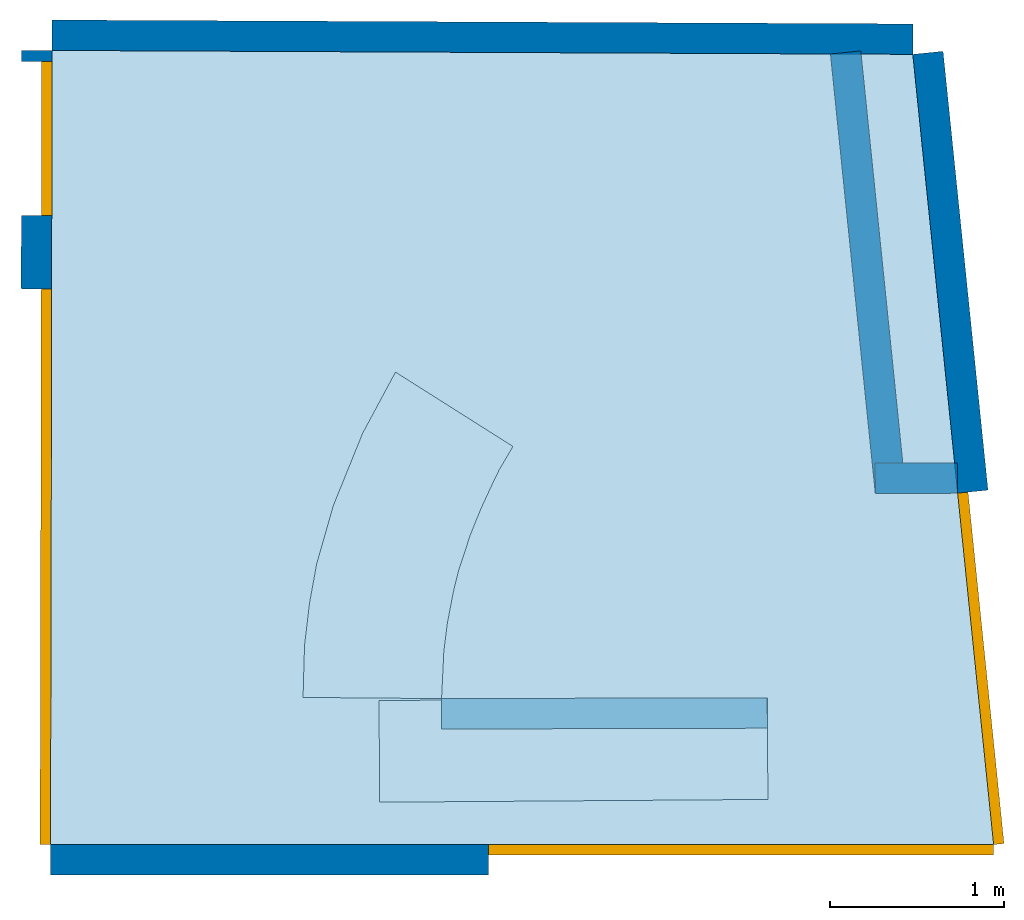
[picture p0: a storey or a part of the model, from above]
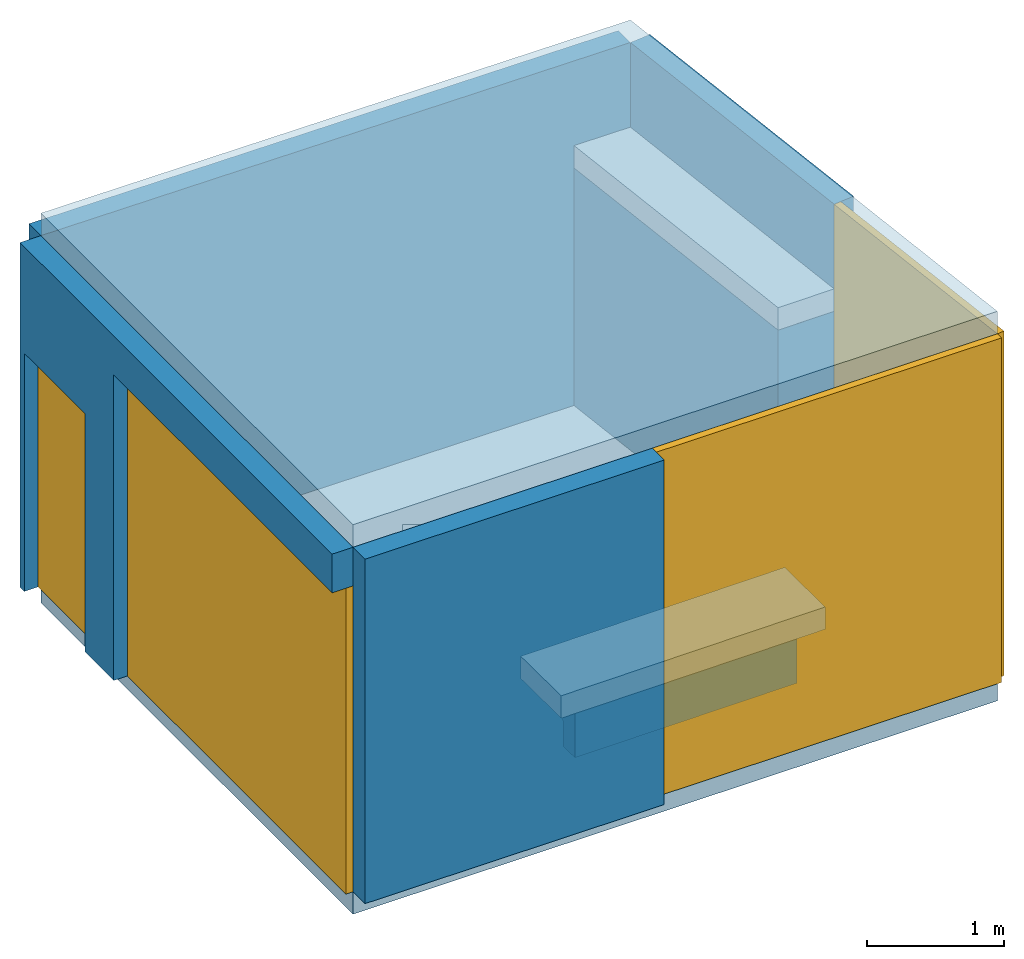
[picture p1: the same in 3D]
Properties of the parts of a building model (IFC2X3)

# File
Description: ViewDefinition[CoordinationView_V2.0]
File name: C:\Users\d.jacob\Desktop\IFC Büro test.ifc
Time: 2021-11-10T16:20:00
Written by: IFC 2x3 writer version 1.1
Made in: IFCExportDemo.exe

# IfcBuildingStorey, EG
In: Gebäude [bimCAD App]
Elevation: 0 m

# IfcDoor (3)
In: EG
Name | OverallHeight (m) | OverallWidth (m)
Door | 3.06438 | 2.03059
Door | 3.06438 | 2.90426
Door | 2.11808 | 0.885734

# IfcSlab (5)
In: EG
PredefinedType: FLOOR
Name
3 x Ceiling
2 x Ground

# IfcWindow, Window
In: EG
OverallHeight: 2.71979 m; OverallWidth: 3.19506 m
